One B-rep face of a CAD part: STEP entity #213.
In plain terms, the planar face has unit normal (0, 0, 1).
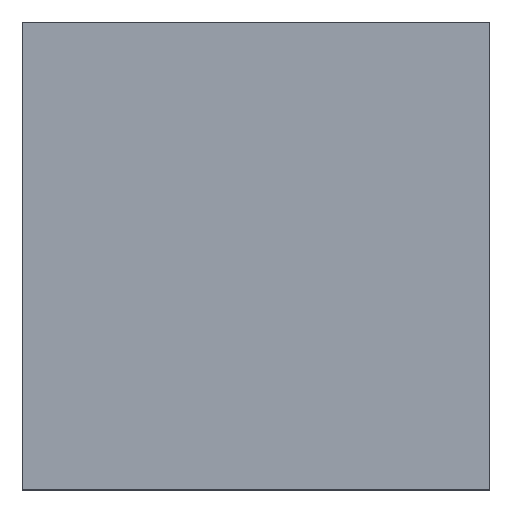
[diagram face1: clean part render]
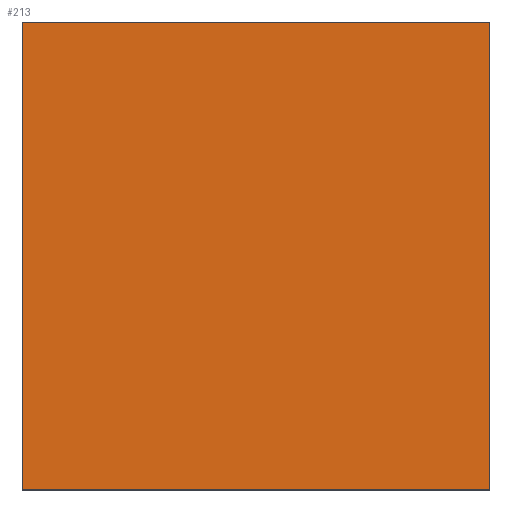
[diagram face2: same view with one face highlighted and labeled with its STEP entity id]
Its self-contained STEP definition (entity closure, numbers rounded to 3 decimals):
#24 = VERTEX_POINT('',#25);
#25 = CARTESIAN_POINT('',(-14.,-14.,60.));
#32 = PLANE('',#33);
#33 = AXIS2_PLACEMENT_3D('',#34,#35,#36);
#34 = CARTESIAN_POINT('',(-14.,-14.,54.));
#35 = DIRECTION('',(1.,0.,0.));
#36 = DIRECTION('',(0.,0.,1.));
#44 = PLANE('',#45);
#45 = AXIS2_PLACEMENT_3D('',#46,#47,#48);
#46 = CARTESIAN_POINT('',(-14.,-14.,54.));
#47 = DIRECTION('',(0.,1.,0.));
#48 = DIRECTION('',(0.,0.,1.));
#85 = VERTEX_POINT('',#86);
#86 = CARTESIAN_POINT('',(-14.,14.,60.));
#100 = PLANE('',#101);
#101 = AXIS2_PLACEMENT_3D('',#102,#103,#104);
#102 = CARTESIAN_POINT('',(-14.,14.,54.));
#103 = DIRECTION('',(0.,1.,0.));
#104 = DIRECTION('',(0.,0.,1.));
#112 = EDGE_CURVE('',#24,#85,#113,.T.);
#113 = SURFACE_CURVE('',#114,(#118,#125),.PCURVE_S1.);
#114 = LINE('',#115,#116);
#115 = CARTESIAN_POINT('',(-14.,-14.,60.));
#116 = VECTOR('',#117,1.);
#117 = DIRECTION('',(0.,1.,0.));
#118 = PCURVE('',#32,#119);
#119 = DEFINITIONAL_REPRESENTATION('',(#120),#124);
#120 = LINE('',#121,#122);
#121 = CARTESIAN_POINT('',(6.,0.));
#122 = VECTOR('',#123,1.);
#123 = DIRECTION('',(0.,-1.));
#124 = ( GEOMETRIC_REPRESENTATION_CONTEXT(2) 
PARAMETRIC_REPRESENTATION_CONTEXT() REPRESENTATION_CONTEXT('2D SPACE',''
  ) );
#125 = PCURVE('',#126,#131);
#126 = PLANE('',#127);
#127 = AXIS2_PLACEMENT_3D('',#128,#129,#130);
#128 = CARTESIAN_POINT('',(-14.,-14.,60.));
#129 = DIRECTION('',(0.,0.,1.));
#130 = DIRECTION('',(1.,0.,0.));
#131 = DEFINITIONAL_REPRESENTATION('',(#132),#136);
#132 = LINE('',#133,#134);
#133 = CARTESIAN_POINT('',(0.,0.));
#134 = VECTOR('',#135,1.);
#135 = DIRECTION('',(0.,1.));
#136 = ( GEOMETRIC_REPRESENTATION_CONTEXT(2) 
PARAMETRIC_REPRESENTATION_CONTEXT() REPRESENTATION_CONTEXT('2D SPACE',''
  ) );
#165 = EDGE_CURVE('',#24,#166,#168,.T.);
#166 = VERTEX_POINT('',#167);
#167 = CARTESIAN_POINT('',(14.,-14.,60.));
#168 = SURFACE_CURVE('',#169,(#173,#180),.PCURVE_S1.);
#169 = LINE('',#170,#171);
#170 = CARTESIAN_POINT('',(-14.,-14.,60.));
#171 = VECTOR('',#172,1.);
#172 = DIRECTION('',(1.,0.,0.));
#173 = PCURVE('',#44,#174);
#174 = DEFINITIONAL_REPRESENTATION('',(#175),#179);
#175 = LINE('',#176,#177);
#176 = CARTESIAN_POINT('',(6.,0.));
#177 = VECTOR('',#178,1.);
#178 = DIRECTION('',(0.,1.));
#179 = ( GEOMETRIC_REPRESENTATION_CONTEXT(2) 
PARAMETRIC_REPRESENTATION_CONTEXT() REPRESENTATION_CONTEXT('2D SPACE',''
  ) );
#180 = PCURVE('',#126,#181);
#181 = DEFINITIONAL_REPRESENTATION('',(#182),#186);
#182 = LINE('',#183,#184);
#183 = CARTESIAN_POINT('',(0.,0.));
#184 = VECTOR('',#185,1.);
#185 = DIRECTION('',(1.,0.));
#186 = ( GEOMETRIC_REPRESENTATION_CONTEXT(2) 
PARAMETRIC_REPRESENTATION_CONTEXT() REPRESENTATION_CONTEXT('2D SPACE',''
  ) );
#202 = PLANE('',#203);
#203 = AXIS2_PLACEMENT_3D('',#204,#205,#206);
#204 = CARTESIAN_POINT('',(14.,-14.,54.));
#205 = DIRECTION('',(1.,0.,0.));
#206 = DIRECTION('',(0.,0.,1.));
#213 = ADVANCED_FACE('',(#214),#126,.T.);
#214 = FACE_BOUND('',#215,.T.);
#215 = EDGE_LOOP('',(#216,#217,#218,#241));
#216 = ORIENTED_EDGE('',*,*,#112,.F.);
#217 = ORIENTED_EDGE('',*,*,#165,.T.);
#218 = ORIENTED_EDGE('',*,*,#219,.T.);
#219 = EDGE_CURVE('',#166,#220,#222,.T.);
#220 = VERTEX_POINT('',#221);
#221 = CARTESIAN_POINT('',(14.,14.,60.));
#222 = SURFACE_CURVE('',#223,(#227,#234),.PCURVE_S1.);
#223 = LINE('',#224,#225);
#224 = CARTESIAN_POINT('',(14.,-14.,60.));
#225 = VECTOR('',#226,1.);
#226 = DIRECTION('',(0.,1.,0.));
#227 = PCURVE('',#126,#228);
#228 = DEFINITIONAL_REPRESENTATION('',(#229),#233);
#229 = LINE('',#230,#231);
#230 = CARTESIAN_POINT('',(28.,0.));
#231 = VECTOR('',#232,1.);
#232 = DIRECTION('',(0.,1.));
#233 = ( GEOMETRIC_REPRESENTATION_CONTEXT(2) 
PARAMETRIC_REPRESENTATION_CONTEXT() REPRESENTATION_CONTEXT('2D SPACE',''
  ) );
#234 = PCURVE('',#202,#235);
#235 = DEFINITIONAL_REPRESENTATION('',(#236),#240);
#236 = LINE('',#237,#238);
#237 = CARTESIAN_POINT('',(6.,0.));
#238 = VECTOR('',#239,1.);
#239 = DIRECTION('',(0.,-1.));
#240 = ( GEOMETRIC_REPRESENTATION_CONTEXT(2) 
PARAMETRIC_REPRESENTATION_CONTEXT() REPRESENTATION_CONTEXT('2D SPACE',''
  ) );
#241 = ORIENTED_EDGE('',*,*,#242,.F.);
#242 = EDGE_CURVE('',#85,#220,#243,.T.);
#243 = SURFACE_CURVE('',#244,(#248,#255),.PCURVE_S1.);
#244 = LINE('',#245,#246);
#245 = CARTESIAN_POINT('',(-14.,14.,60.));
#246 = VECTOR('',#247,1.);
#247 = DIRECTION('',(1.,0.,0.));
#248 = PCURVE('',#126,#249);
#249 = DEFINITIONAL_REPRESENTATION('',(#250),#254);
#250 = LINE('',#251,#252);
#251 = CARTESIAN_POINT('',(0.,28.));
#252 = VECTOR('',#253,1.);
#253 = DIRECTION('',(1.,0.));
#254 = ( GEOMETRIC_REPRESENTATION_CONTEXT(2) 
PARAMETRIC_REPRESENTATION_CONTEXT() REPRESENTATION_CONTEXT('2D SPACE',''
  ) );
#255 = PCURVE('',#100,#256);
#256 = DEFINITIONAL_REPRESENTATION('',(#257),#261);
#257 = LINE('',#258,#259);
#258 = CARTESIAN_POINT('',(6.,0.));
#259 = VECTOR('',#260,1.);
#260 = DIRECTION('',(0.,1.));
#261 = ( GEOMETRIC_REPRESENTATION_CONTEXT(2) 
PARAMETRIC_REPRESENTATION_CONTEXT() REPRESENTATION_CONTEXT('2D SPACE',''
  ) );
